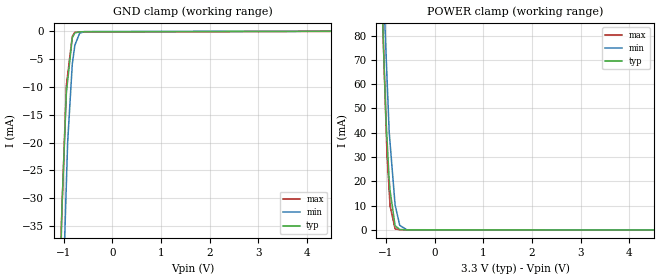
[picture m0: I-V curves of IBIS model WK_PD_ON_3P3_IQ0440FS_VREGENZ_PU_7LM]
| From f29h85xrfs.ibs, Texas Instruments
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|RECEIVER_MODE_3P3; RECEIVER_MODE
|   Model Cell WK_PD_ON_3P3_IQ0440FS_VREGENZ_PU_7LM
|WK_PD_ON_3P3_IQ0440FS_VREGENZ_PU_7LM
[Model]   WK_PD_ON_3P3_IQ0440FS_VREGENZ_PU_7LM
Model_type   Input
Polarity   Non-Inverting
Vinl = 0.8
Vinh = 2
|   typ   min   max
C_comp   0.213pF   0.2pF   0.24pF
[Model Spec]
Vinl   0.8   0.8   0.8
Vinh   2   2   2
[Temperature Range]   25   155   -40
[Voltage Range]   3.3   2.8   3.63
| Nom Voltages:
|   VDD=1.23, VDDS=3.3, VSS=0
| Min Voltages:
|   VDD=1.08, VDDS=2.8, VSS=0
| Max Voltages:
|   VDD=1.32, VDDS=3.63, VSS=0
[Power Clamp Reference]   3.3   2.8   3.63
[GND Clamp Reference]   0   0   0
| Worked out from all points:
|   GND clamp passes 1 mA (typ) near -0.81 V on its own axis
|   POWER clamp passes 1 mA (typ) near -0.79 V on its own axis
[GND Clamp]
|   Voltage   I(typ)   I(min)   I(max)
-3.3V     -1.431A    -1.17A     -2.111A
-1.057V   -41.27mA   -63.96mA   -38.92mA
-1.049V   -37.96mA   -60.95mA   -35.78mA
-1.032V   -31.37mA   -54.15mA   -31.57mA
-1.014V   -27.28mA   -47.81mA   -27.31mA
-942.4mV  -11.12mA   -27.44mA   -9.782mA
-916.1mV  -8.923mA   -19.99mA   -7.871mA
-821mV    -1.199mA   -5.938mA   -962.8uA
-767.9mV  -348.4uA   -2.535mA   -221.8uA
-670.8mV  -121.1uA   -411.6uA   -172.1uA
-575.5mV  -113.4uA   -93.36uA   -170.7uA
6.6V      0A         0A         0A
[POWER Clamp]
|   Voltage   I(typ)   I(min)   I(max)
-3.3V     1.901A     2.211A     2.057A
-1.072V   87.57mA    117.4mA    87.66mA
-1.037V   66.06mA    92.05mA    65.42mA
-1.025V   59.06mA    84.98mA    58.19mA
-1.002V   45.94mA    73.43mA    43.54mA
-981mV    37.9mA     62.96mA    31.39mA
-935.6mV  20.53mA    40.34mA    15.95mA
-917.8mV  16.29mA    35.83mA    9.924mA
-814.5mV  1.778mA    10.35mA    434.5uA
-718.9mV  170.5uA    1.896mA    100.3uA
-575.5mV  62.86uA    90.44uA    74.71uA
6.6V      0A         0A         0A
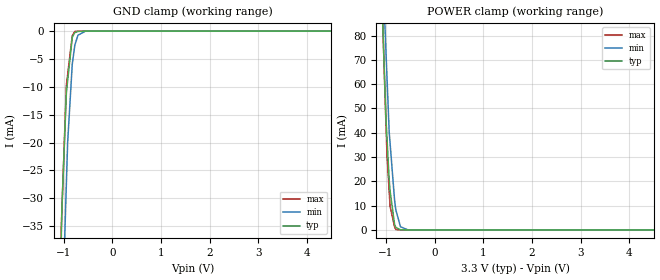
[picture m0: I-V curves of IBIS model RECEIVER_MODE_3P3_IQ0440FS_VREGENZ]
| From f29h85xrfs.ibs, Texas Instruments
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|   Model Cell RECEIVER_MODE_3P3_IQ0440FS_VREGENZ
|RECEIVER_MODE_3P3_IQ0440FS_VREGENZ
[Model]   RECEIVER_MODE_3P3_IQ0440FS_VREGENZ
Model_type   Input
Polarity   Non-Inverting
Vinl = 0.8
Vinh = 2
|   typ   min   max
C_comp   0.213pF   0.2pF   0.24pF
[Model Spec]
Vinl   0.8   0.8   0.8
Vinh   2   2   2
[Temperature Range]   25   155   -40
[Voltage Range]   3.3   2.8   3.63
| Nom Voltages:
|   VDD=1.23, VDDS=3.3, VSS=0
| Min Voltages:
|   VDD=1.08, VDDS=2.8, VSS=0
| Max Voltages:
|   VDD=1.32, VDDS=3.63, VSS=0
[Power Clamp Reference]   3.3   2.8   3.63
[GND Clamp Reference]   0   0   0
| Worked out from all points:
|   GND clamp passes 1 mA (typ) near -0.82 V on its own axis
|   POWER clamp passes 1 mA (typ) near -0.80 V on its own axis
[GND Clamp]
|   Voltage   I(typ)   I(min)   I(max)
-3.3V     -1.431A    -1.17A     -2.111A
-1.057V   -41.25mA   -63.95mA   -38.9mA
-1.049V   -37.93mA   -60.95mA   -35.77mA
-1.032V   -31.34mA   -54.14mA   -31.54mA
-1.014V   -27.25mA   -47.79mA   -27.28mA
-942.5mV  -11.09mA   -27.44mA   -9.753mA
-916.1mV  -8.881mA   -19.98mA   -7.815mA
-821mV    -1.121mA   -5.917mA   -829.9uA
-768mV    -261.2uA   -2.517mA   -64.37uA
-704.1mV  -57.42uA   -743.1uA   -24.31uA
-553.5mV  -1.175uA   -26.97uA   -4.078uA
6.6V      0A         0A         0A
[POWER Clamp]
|   Voltage   I(typ)   I(min)   I(max)
-3.3V     1.901A     2.211A     2.057A
-1.072V   87.53mA    117.4mA    87.59mA
-1.025V   58.99mA    84.95mA    58.07mA
-1.002V   45.88mA    73.4mA     43.43mA
-981.1mV  37.85mA    62.95mA    31.29mA
-935.5mV  20.45mA    40.3mA     15.82mA
-917.9mV  16.22mA    35.82mA    9.821mA
-824.6mV  2.252mA    12.17mA    1.25mA
-800.1mV  1.104mA    8.357mA    176.7uA
-704.1mV  75.45uA    1.343mA    12.14uA
-553.5mV  842.6nA    34.39uA    2.541uA
6.6V      0A         0A         0A
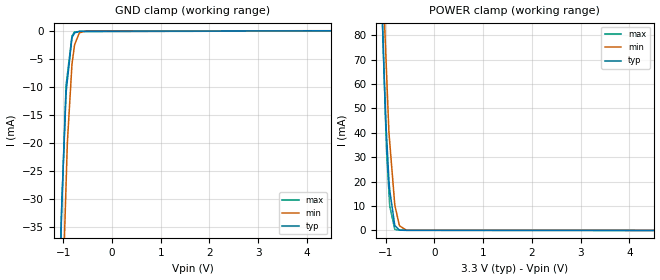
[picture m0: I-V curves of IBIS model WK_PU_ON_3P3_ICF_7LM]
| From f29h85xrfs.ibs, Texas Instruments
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|   Model Cell WK_PU_ON_3P3_ICF_7LM
|WK_PU_ON_3P3_ICF_7LM
[Model]   WK_PU_ON_3P3_ICF_7LM
Model_type   Input
Polarity   Non-Inverting
Vinl = 0.8
Vinh = 2
|   typ   min   max
C_comp   0.213pF   0.2pF   0.23pF
[Model Spec]
Vinl   0.8   0.8   0.8
Vinh   2   2   2
[Temperature Range]   25   155   -40
[Voltage Range]   3.3   2.8   3.63
| Nom Voltages:
|   BIASFET=3.3, VDD=1.2, VDDS=3.3, VSS=0
| Min Voltages:
|   BIASFET=2.8, VDD=1.08, VDDS=2.8, VSS=0
| Max Voltages:
|   BIASFET=3.63, VDD=1.32, VDDS=3.63, VSS=0
[Power Clamp Reference]   3.3   2.8   3.63
[GND Clamp Reference]   0   0   0
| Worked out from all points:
|   GND clamp passes 1 mA (typ) near -0.81 V on its own axis
|   POWER clamp passes 1 mA (typ) near -0.78 V on its own axis
[GND Clamp]
|   Voltage   I(typ)   I(min)   I(max)
-3.3V     -1.431A    -1.17A     -2.111A
-1.057V   -41.27mA   -63.95mA   -38.92mA
-1.049V   -37.96mA   -60.95mA   -35.79mA
-1.032V   -31.37mA   -54.15mA   -31.57mA
-1.014V   -27.28mA   -47.81mA   -27.32mA
-942.4mV  -11.12mA   -27.44mA   -9.786mA
-916.1mV  -8.927mA   -19.99mA   -7.877mA
-821mV    -1.234mA   -5.939mA   -974.6uA
-767.9mV  -439.1uA   -2.537mA   -234.6uA
-670.8mV  -125.9uA   -415.1uA   -184.9uA
-542mV    -115.8uA   -74.66uA   -183.8uA
6.6V      0A         0A         0A
[POWER Clamp]
|   Voltage   I(typ)   I(min)   I(max)
-3.3V     1.901A     2.211A     2.057A
-1.072V   87.57mA    117.4mA    87.67mA
-1.037V   66.06mA    92.06mA    65.43mA
-1.025V   59.07mA    84.99mA    58.19mA
-1.002V   45.95mA    73.43mA    43.55mA
-981mV    37.91mA    62.96mA    31.4mA
-935.6mV  20.54mA    40.34mA    15.96mA
-917.8mV  16.29mA    35.84mA    9.932mA
-814.5mV  2.031mA    10.35mA    441.5uA
-718.8mV  148.5uA    1.899mA    106uA
-575.5mV  58.6uA     92.58uA    79.43uA
6.6V      0A         0A         0A
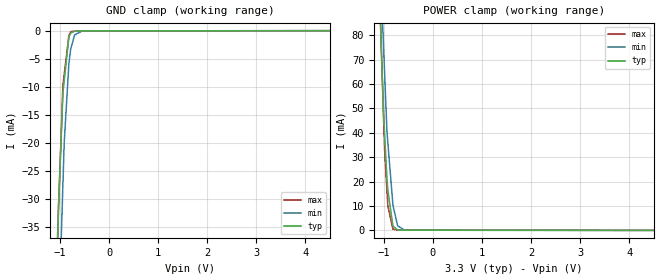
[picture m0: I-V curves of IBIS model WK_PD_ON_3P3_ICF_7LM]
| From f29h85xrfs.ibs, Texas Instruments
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|   Model Cell WK_PD_ON_3P3_ICF_7LM
|WK_PD_ON_3P3_ICF_7LM
[Model]   WK_PD_ON_3P3_ICF_7LM
Model_type   Input
Polarity   Non-Inverting
Vinl = 0.8
Vinh = 2
|   typ   min   max
C_comp   0.213pF   0.2pF   0.23pF
[Model Spec]
Vinl   0.8   0.8   0.8
Vinh   2   2   2
[Temperature Range]   25   155   -40
[Voltage Range]   3.3   2.8   3.63
| Nom Voltages:
|   BIASFET=3.3, VDD=1.2, VDDS=3.3, VSS=0
| Min Voltages:
|   BIASFET=2.8, VDD=1.08, VDDS=2.8, VSS=0
| Max Voltages:
|   BIASFET=3.63, VDD=1.32, VDDS=3.63, VSS=0
[Power Clamp Reference]   3.3   2.8   3.63
[GND Clamp Reference]   0   0   0
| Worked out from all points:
|   GND clamp passes 1 mA (typ) near -0.81 V on its own axis
|   POWER clamp passes 1 mA (typ) near -0.79 V on its own axis
[GND Clamp]
|   Voltage   I(typ)   I(min)   I(max)
-3.3V     -1.431A    -1.17A     -2.111A
-1.057V   -41.26mA   -63.95mA   -38.91mA
-1.049V   -37.95mA   -60.95mA   -35.77mA
-1.032V   -31.36mA   -54.14mA   -31.56mA
-1.014V   -27.27mA   -47.8mA    -27.3mA
-942.4mV  -11.11mA   -27.43mA   -9.764mA
-916.1mV  -8.911mA   -19.99mA   -7.843mA
-821.1mV  -1.165mA   -5.933mA   -901.7uA
-784.8mV  -475.6uA   -3.357mA   -200.7uA
-704.1mV  -103.5uA   -766.2uA   -94.99uA
-542.1mV  -53.37uA   -49.27uA   -65.97uA
6.6V      0A         0A         0A
[POWER Clamp]
|   Voltage   I(typ)   I(min)   I(max)
-3.3V     1.901A     2.211A     2.057A
-1.072V   87.58mA    117.4mA    87.69mA
-1.037V   66.07mA    92.05mA    65.45mA
-1.025V   59.07mA    84.98mA    58.22mA
-1.002V   45.95mA    73.42mA    43.57mA
-981mV    37.92mA    62.96mA    31.42mA
-935.6mV  20.56mA    40.34mA    15.99mA
-917.8mV  16.31mA    35.83mA    9.968mA
-814.5mV  1.809mA    10.35mA    490.3uA
-718.9mV  185.8uA    1.905mA    176.7uA
-575.5mV  112.6uA    106.6uA    161.5uA
6.6V      0A         0A         0A
